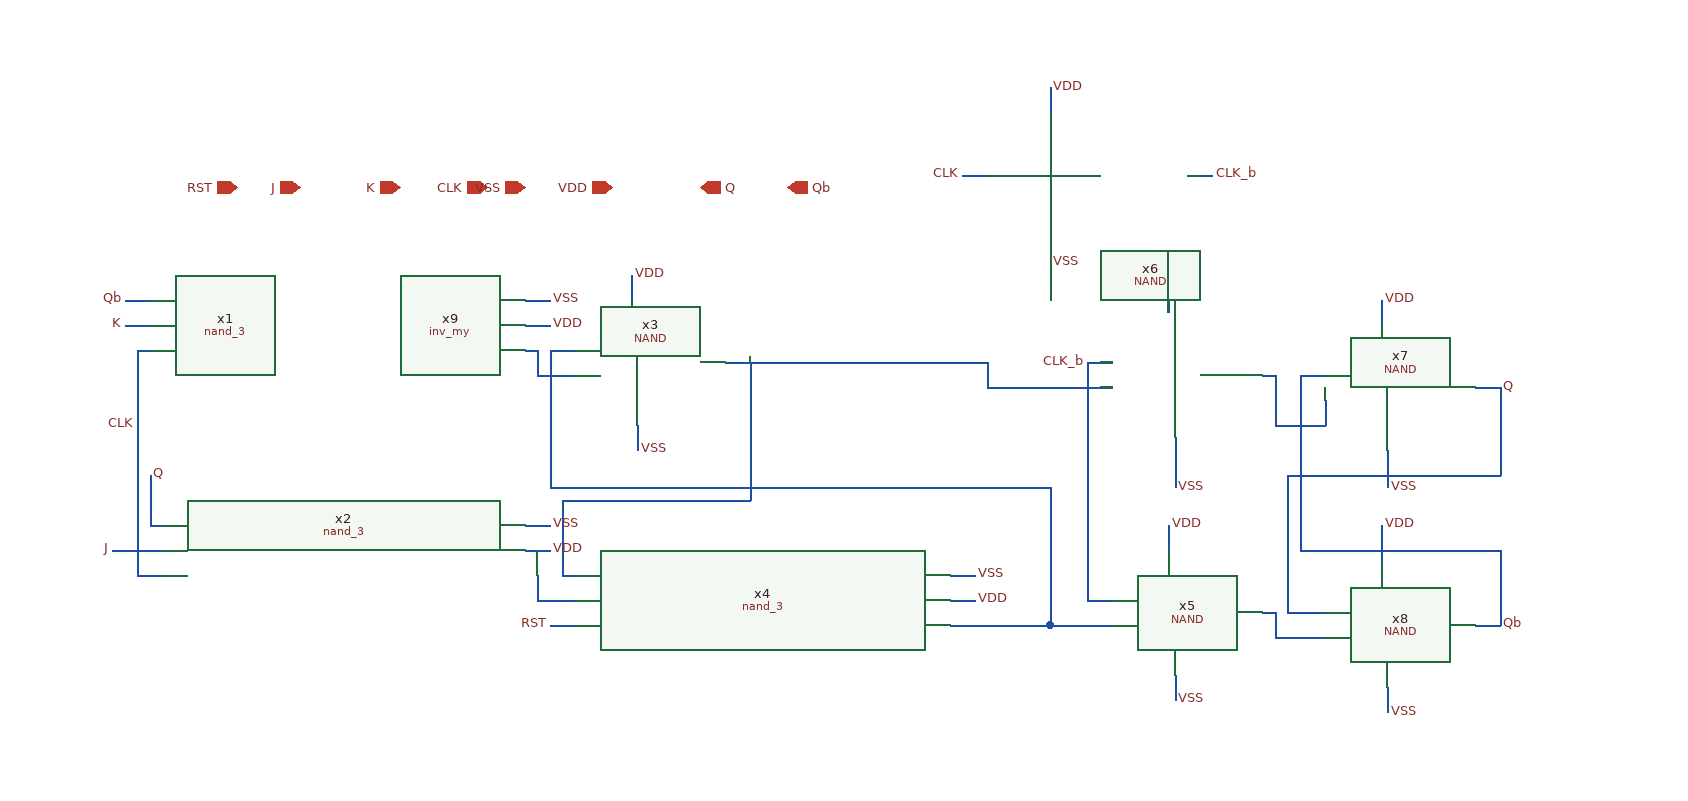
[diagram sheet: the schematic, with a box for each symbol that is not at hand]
v {xschem version=3.1.0 file_version=1.2
}
G {}
K {}
V {}
S {}
E {}
N 560 -290 760 -290 {
lab=#net1}
N 730 -80 770 -80 {
lab=#net2}
N 1160 -80 1170 -80 {
lab=Qb}
N 1170 -140 1170 -80 {
lab=Qb}
N 1010 -140 1170 -140 {
lab=Qb}
N 1010 -260 1010 -180 {
lab=Qb}
N 1160 -270 1170 -270 {
lab=Q}
N 1170 -270 1170 -210 {
lab=Q}
N 1000 -200 1160 -200 {
lab=Q}
N 570 -290 570 -220 {
lab=#net1}
N 420 -180 570 -180 {
lab=#net1}
N 420 -100 430 -100 {
lab=#net3}
N 420 -190 740 -190 {
lab=#net2}
N 80 -300 90 -300 {
lab=CLK}
N 1010 -180 1010 -140 {
lab=Qb}
N 570 -220 570 -180 {
lab=#net1}
N 410 -230 410 -190 {
lab=#net2}
N 1000 -200 1000 -170 {
lab=Q}
N 1170 -210 1170 -200 {
lab=Q}
N 80 -300 80 -160 {
lab=CLK}
N 70 -340 90 -340 {
lab=Qb}
N 390 -340 410 -340 {
lab=VSS}
N 390 -320 410 -320 {
lab=VDD}
N 390 -160 410 -160 {
lab=VSS}
N 390 -140 410 -140 {
lab=VDD}
N 475 -360 475 -340 {
lab=VDD}
N 480 -240 480 -220 {
lab=VSS}
N 850 -100 860 -100 {
lab=CLK_b}
N 410 -80 430 -80 {
lab=RST}
N 730 -120 750 -120 {
lab=VSS}
N 730 -100 750 -100 {
lab=VDD}
N 905 -350 905 -330 {
lab=VDD}
N 910 -230 910 -190 {
lab=VSS}
N 905 -160 905 -140 {
lab=VDD}
N 910 -40 910 -20 {
lab=VSS}
N 1075 -340 1075 -320 {
lab=VDD}
N 1080 -220 1080 -190 {
lab=VSS}
N 1075 -160 1075 -130 {
lab=VDD}
N 1080 -30 1080 -10 {
lab=VSS}
N 1160 -200 1170 -200 {
lab=Q}
N 850 -290 860 -290 {
lab=CLK_b}
N 740 -440 760 -440 {
lab=CLK}
N 920 -440 940 -440 {
lab=CLK_b}
N 810 -510 810 -490 {
lab=VDD}
N 810 -390 810 -370 {
lab=VSS}
N 1150 -80 1160 -80 {
lab=Qb}
N 1150 -270 1160 -270 {
lab=Q}
N 980 -280 990 -280 {
lab=#net4}
N 980 -90 990 -90 {
lab=#net5}
N 550 -290 560 -290 {
lab=#net1}
N 80 -120 90 -120 {
lab=CLK}
N 60 -140 100 -140 {
lab=J}
N 90 -120 100 -120 {
lab=CLK}
N 80 -160 80 -120 {
lab=CLK}
N 70 -320 90 -320 {
lab=K}
N 90 -160 100 -160 {
lab=Q}
N 90 -200 90 -160 {
lab=Q}
N 400 -100 420 -100 {
lab=#net3}
N 400 -120 400 -100 {
lab=#net3}
N 420 -180 420 -120 {
lab=#net1}
N 420 -120 430 -120 {
lab=#net1}
N 420 -300 430 -300 {
lab=#net2}
N 390 -300 400 -300 {
lab=#net6}
N 400 -300 400 -280 {
lab=#net6}
N 400 -280 430 -280 {
lab=#net6}
N 410 -300 420 -300 {
lab=#net2}
N 410 -300 410 -230 {
lab=#net2}
N 410 -190 420 -190 {
lab=#net2}
N 760 -290 760 -270 {
lab=#net1}
N 760 -270 860 -270 {
lab=#net1}
N 840 -100 850 -100 {
lab=CLK_b}
N 840 -140 840 -100 {
lab=CLK_b}
N 840 -290 840 -140 {
lab=CLK_b}
N 840 -290 850 -290 {
lab=CLK_b}
N 740 -190 810 -190 {
lab=#net2}
N 810 -190 810 -80 {
lab=#net2}
N 770 -80 810 -80 {
lab=#net2}
N 810 -80 860 -80 {
lab=#net2}
N 990 -70 1030 -70 {
lab=#net5}
N 990 -90 990 -70 {
lab=#net5}
N 1000 -90 1030 -90 {
lab=Q}
N 1000 -170 1000 -90 {
lab=Q}
N 1010 -280 1010 -260 {
lab=Qb}
N 1010 -280 1030 -280 {
lab=Qb}
N 990 -280 990 -260 {
lab=#net4}
N 1030 -260 1030 -240 {
lab=#net4}
N 990 -240 1030 -240 {
lab=#net4}
N 990 -260 990 -240 {
lab=#net4}
C {nand_3.sym} 240 -320 0 0 {name=x1}
C {nand_3.sym} 250 -140 0 0 {name=x2}
C {nand_3.sym} 580 -100 0 0 {name=x4}
C {devices/ipin.sym} 290 -430 0 0 {name=p1 lab=K}
C {devices/ipin.sym} 360 -430 0 0 {name=p2 lab=CLK}
C {devices/iopin.sym} 390 -430 0 0 {name=p3 lab=VSS
}
C {devices/iopin.sym} 460 -430 0 0 {name=p4 lab=VDD}
C {devices/opin.sym} 530 -430 0 0 {name=p5 lab=Q}
C {devices/ipin.sym} 210 -430 0 0 {name=p19 lab=J}
C {devices/lab_pin.sym} 70 -320 0 0 {name=p6 sig_type=std_logic lab=K}
C {devices/lab_pin.sym} 60 -140 0 0 {name=p7 sig_type=std_logic lab=J}
C {devices/lab_pin.sym} 410 -80 0 0 {name=p8 sig_type=std_logic lab=RST}
C {devices/lab_pin.sym} 80 -240 0 0 {name=p9 sig_type=std_logic lab=CLK}
C {devices/lab_pin.sym} 410 -340 2 0 {name=p10 sig_type=std_logic lab=VSS}
C {devices/lab_pin.sym} 410 -320 2 0 {name=p11 sig_type=std_logic lab=VDD}
C {devices/lab_pin.sym} 475 -360 2 0 {name=p12 sig_type=std_logic lab=VDD}
C {devices/lab_pin.sym} 480 -220 2 0 {name=p13 sig_type=std_logic lab=VSS}
C {devices/lab_pin.sym} 410 -160 2 0 {name=p14 sig_type=std_logic lab=VSS}
C {devices/lab_pin.sym} 910 -190 2 0 {name=p15 sig_type=std_logic lab=VSS}
C {devices/lab_pin.sym} 750 -120 2 0 {name=p16 sig_type=std_logic lab=VSS}
C {devices/lab_pin.sym} 1080 -10 2 0 {name=p17 sig_type=std_logic lab=VSS}
C {devices/lab_pin.sym} 1080 -190 2 0 {name=p18 sig_type=std_logic lab=VSS}
C {devices/lab_pin.sym} 910 -20 2 0 {name=p20 sig_type=std_logic lab=VSS}
C {devices/lab_pin.sym} 410 -140 2 0 {name=p21 sig_type=std_logic lab=VDD}
C {devices/lab_pin.sym} 750 -100 2 0 {name=p22 sig_type=std_logic lab=VDD}
C {devices/lab_pin.sym} 905 -350 2 0 {name=p23 sig_type=std_logic lab=VDD}
C {devices/lab_pin.sym} 1075 -340 2 0 {name=p24 sig_type=std_logic lab=VDD}
C {devices/lab_pin.sym} 1075 -160 2 0 {name=p25 sig_type=std_logic lab=VDD}
C {devices/lab_pin.sym} 905 -160 2 0 {name=p26 sig_type=std_logic lab=VDD}
C {devices/opin.sym} 600 -430 0 0 {name=p27 lab=Qb}
C {devices/lab_pin.sym} 1170 -270 2 0 {name=p28 sig_type=std_logic lab=Q}
C {devices/lab_pin.sym} 1170 -80 2 0 {name=p29 sig_type=std_logic lab=Qb}
C {devices/ipin.sym} 160 -430 0 0 {name=p30 lab=RST}
C {devices/lab_pin.sym} 740 -440 0 0 {name=p31 sig_type=std_logic lab=CLK}
C {devices/lab_pin.sym} 940 -440 2 0 {name=p32 sig_type=std_logic lab=CLK_b}
C {devices/lab_pin.sym} 810 -510 2 0 {name=p33 sig_type=std_logic lab=VDD}
C {devices/lab_pin.sym} 810 -370 2 0 {name=p34 sig_type=std_logic lab=VSS}
C {devices/lab_pin.sym} 840 -290 0 0 {name=p35 sig_type=std_logic lab=CLK_b}
C {NAND.sym} 510 -260 0 0 {name=x3}
C {NAND.sym} 940 -60 0 0 {name=x5}
C {NAND.sym} 940 -250 0 0 {name=x6}
C {NAND.sym} 1110 -240 0 0 {name=x7}
C {NAND.sym} 1110 -50 0 0 {name=x8}
C {devices/lab_pin.sym} 70 -340 0 0 {name=p36 sig_type=std_logic lab=Qb}
C {devices/lab_pin.sym} 90 -200 2 0 {name=p37 sig_type=std_logic lab=Q}
C {inv_my.sym} 320 -310 0 0 {name=x9}
